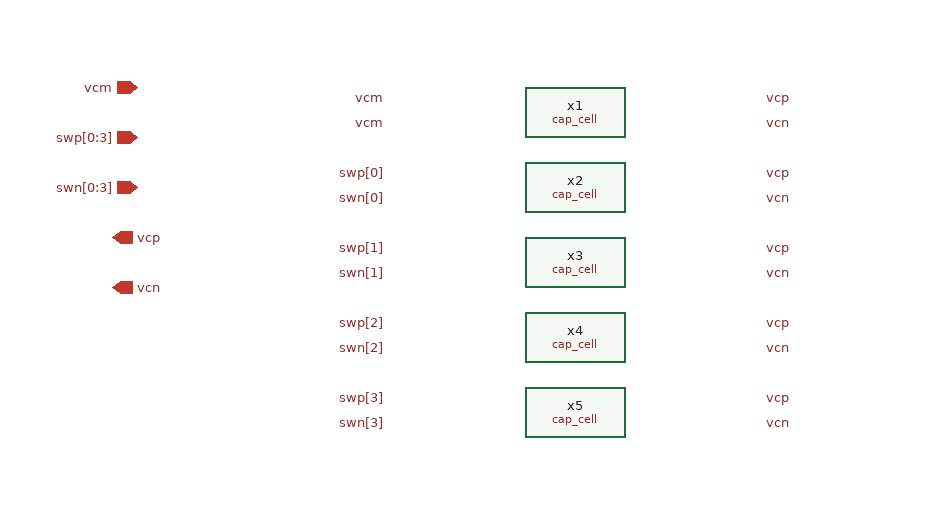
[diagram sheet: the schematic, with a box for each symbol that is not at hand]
v {xschem version=3.4.5 file_version=1.2
}
G {}
K {}
V {}
S {}
E {}
C {cap_cell.sym} 570 -460 0 0 {name=x1 dim=1u num=1}
C {cap_cell.sym} 570 -400 0 0 {name=x2 dim=1u num=1}
C {cap_cell.sym} 570 -340 0 0 {name=x3 dim=1u num=2}
C {cap_cell.sym} 570 -280 0 0 {name=x4 dim=1u num=4}
C {cap_cell.sym} 570 -220 0 0 {name=x5 dim=1u num=8}
C {devices/lab_wire.sym} 720 -470 0 1 {name=p1 sig_type=std_logic lab=vcp}
C {devices/lab_wire.sym} 720 -450 0 1 {name=p2 sig_type=std_logic lab=vcn}
C {devices/lab_wire.sym} 720 -410 0 1 {name=p3 sig_type=std_logic lab=vcp}
C {devices/lab_wire.sym} 720 -390 0 1 {name=p4 sig_type=std_logic lab=vcn}
C {devices/lab_wire.sym} 720 -350 0 1 {name=p5 sig_type=std_logic lab=vcp}
C {devices/lab_wire.sym} 720 -330 0 1 {name=p6 sig_type=std_logic lab=vcn}
C {devices/lab_wire.sym} 720 -290 0 1 {name=p7 sig_type=std_logic lab=vcp}
C {devices/lab_wire.sym} 720 -270 0 1 {name=p8 sig_type=std_logic lab=vcn}
C {devices/lab_wire.sym} 720 -230 0 1 {name=p9 sig_type=std_logic lab=vcp}
C {devices/lab_wire.sym} 720 -210 0 1 {name=p10 sig_type=std_logic lab=vcn}
C {devices/lab_wire.sym} 420 -470 0 0 {name=p11 sig_type=std_logic lab=vcm}
C {devices/lab_wire.sym} 420 -450 0 0 {name=p12 sig_type=std_logic lab=vcm}
C {devices/lab_wire.sym} 420 -410 0 0 {name=p13 sig_type=std_logic lab=swp[0]}
C {devices/lab_wire.sym} 420 -390 0 0 {name=p14 sig_type=std_logic lab=swn[0]}
C {devices/lab_wire.sym} 420 -350 0 0 {name=p15 sig_type=std_logic lab=swp[1]}
C {devices/lab_wire.sym} 420 -330 0 0 {name=p16 sig_type=std_logic lab=swn[1]}
C {devices/lab_wire.sym} 420 -290 0 0 {name=p17 sig_type=std_logic lab=swp[2]}
C {devices/lab_wire.sym} 420 -270 0 0 {name=p18 sig_type=std_logic lab=swn[2]}
C {devices/lab_wire.sym} 420 -230 0 0 {name=p19 sig_type=std_logic lab=swp[3]}
C {devices/lab_wire.sym} 420 -210 0 0 {name=p20 sig_type=std_logic lab=swn[3]}
C {devices/ipin.sym} 220 -480 0 0 {name=p21 lab=vcm}
C {devices/ipin.sym} 220 -440 0 0 {name=p22 lab=swp[0:3]}
C {devices/ipin.sym} 220 -400 0 0 {name=p23 lab=swn[0:3]}
C {devices/opin.sym} 200 -360 0 0 {name=p24 lab=vcp}
C {devices/opin.sym} 200 -320 0 0 {name=p25 lab=vcn}
